VERSION 5.7 ;
BUSBITCHARS "[]" ;
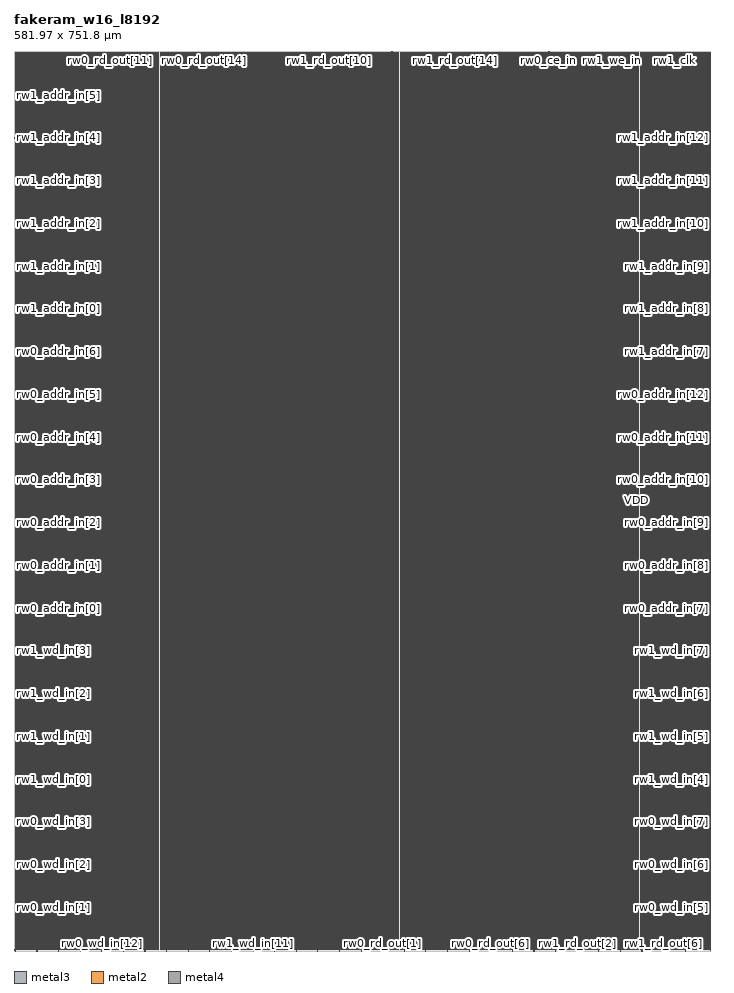
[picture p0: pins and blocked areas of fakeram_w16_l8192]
MACRO fakeram_w16_l8192
  FOREIGN fakeram_w16_l8192 0 0 ;
  SYMMETRY X Y R90 ;
  SIZE 581.970 BY 751.800 ;
  CLASS BLOCK ;
  PIN rw0_wd_in[0]
    DIRECTION INPUT ;
    USE SIGNAL ;
    SHAPE ABUTMENT ;
    PORT
      LAYER metal3 ;
      RECT 0.000 0.805 0.210 0.875 ;
    END
  END rw0_wd_in[0]
  PIN rw0_wd_in[1]
    DIRECTION INPUT ;
    USE SIGNAL ;
    SHAPE ABUTMENT ;
    PORT
      LAYER metal3 ;
      RECT 0.000 36.505 0.210 36.575 ;
    END
  END rw0_wd_in[1]
  PIN rw0_wd_in[2]
    DIRECTION INPUT ;
    USE SIGNAL ;
    SHAPE ABUTMENT ;
    PORT
      LAYER metal3 ;
      RECT 0.000 72.205 0.210 72.275 ;
    END
  END rw0_wd_in[2]
  PIN rw0_wd_in[3]
    DIRECTION INPUT ;
    USE SIGNAL ;
    SHAPE ABUTMENT ;
    PORT
      LAYER metal3 ;
      RECT 0.000 107.905 0.210 107.975 ;
    END
  END rw0_wd_in[3]
  PIN rw0_wd_in[4]
    DIRECTION INPUT ;
    USE SIGNAL ;
    SHAPE ABUTMENT ;
    PORT
      LAYER metal3 ;
      RECT 581.760 0.805 581.970 0.875 ;
    END
  END rw0_wd_in[4]
  PIN rw0_wd_in[5]
    DIRECTION INPUT ;
    USE SIGNAL ;
    SHAPE ABUTMENT ;
    PORT
      LAYER metal3 ;
      RECT 581.760 36.505 581.970 36.575 ;
    END
  END rw0_wd_in[5]
  PIN rw0_wd_in[6]
    DIRECTION INPUT ;
    USE SIGNAL ;
    SHAPE ABUTMENT ;
    PORT
      LAYER metal3 ;
      RECT 581.760 72.205 581.970 72.275 ;
    END
  END rw0_wd_in[6]
  PIN rw0_wd_in[7]
    DIRECTION INPUT ;
    USE SIGNAL ;
    SHAPE ABUTMENT ;
    PORT
      LAYER metal3 ;
      RECT 581.760 107.905 581.970 107.975 ;
    END
  END rw0_wd_in[7]
  PIN rw0_wd_in[8]
    DIRECTION INPUT ;
    USE SIGNAL ;
    SHAPE ABUTMENT ;
    PORT
      LAYER metal2 ;
      RECT 1.105 0.000 1.175 0.210 ;
    END
  END rw0_wd_in[8]
  PIN rw0_wd_in[9]
    DIRECTION INPUT ;
    USE SIGNAL ;
    SHAPE ABUTMENT ;
    PORT
      LAYER metal2 ;
      RECT 19.155 0.000 19.225 0.210 ;
    END
  END rw0_wd_in[9]
  PIN rw0_wd_in[10]
    DIRECTION INPUT ;
    USE SIGNAL ;
    SHAPE ABUTMENT ;
    PORT
      LAYER metal2 ;
      RECT 37.205 0.000 37.275 0.210 ;
    END
  END rw0_wd_in[10]
  PIN rw0_wd_in[11]
    DIRECTION INPUT ;
    USE SIGNAL ;
    SHAPE ABUTMENT ;
    PORT
      LAYER metal2 ;
      RECT 55.255 0.000 55.325 0.210 ;
    END
  END rw0_wd_in[11]
  PIN rw0_wd_in[12]
    DIRECTION INPUT ;
    USE SIGNAL ;
    SHAPE ABUTMENT ;
    PORT
      LAYER metal2 ;
      RECT 73.305 0.000 73.375 0.210 ;
    END
  END rw0_wd_in[12]
  PIN rw0_wd_in[13]
    DIRECTION INPUT ;
    USE SIGNAL ;
    SHAPE ABUTMENT ;
    PORT
      LAYER metal2 ;
      RECT 91.355 0.000 91.425 0.210 ;
    END
  END rw0_wd_in[13]
  PIN rw0_wd_in[14]
    DIRECTION INPUT ;
    USE SIGNAL ;
    SHAPE ABUTMENT ;
    PORT
      LAYER metal2 ;
      RECT 109.405 0.000 109.475 0.210 ;
    END
  END rw0_wd_in[14]
  PIN rw0_wd_in[15]
    DIRECTION INPUT ;
    USE SIGNAL ;
    SHAPE ABUTMENT ;
    PORT
      LAYER metal2 ;
      RECT 127.455 0.000 127.525 0.210 ;
    END
  END rw0_wd_in[15]
  PIN rw1_wd_in[0]
    DIRECTION INPUT ;
    USE SIGNAL ;
    SHAPE ABUTMENT ;
    PORT
      LAYER metal3 ;
      RECT 0.000 143.605 0.210 143.675 ;
    END
  END rw1_wd_in[0]
  PIN rw1_wd_in[1]
    DIRECTION INPUT ;
    USE SIGNAL ;
    SHAPE ABUTMENT ;
    PORT
      LAYER metal3 ;
      RECT 0.000 179.305 0.210 179.375 ;
    END
  END rw1_wd_in[1]
  PIN rw1_wd_in[2]
    DIRECTION INPUT ;
    USE SIGNAL ;
    SHAPE ABUTMENT ;
    PORT
      LAYER metal3 ;
      RECT 0.000 215.005 0.210 215.075 ;
    END
  END rw1_wd_in[2]
  PIN rw1_wd_in[3]
    DIRECTION INPUT ;
    USE SIGNAL ;
    SHAPE ABUTMENT ;
    PORT
      LAYER metal3 ;
      RECT 0.000 250.705 0.210 250.775 ;
    END
  END rw1_wd_in[3]
  PIN rw1_wd_in[4]
    DIRECTION INPUT ;
    USE SIGNAL ;
    SHAPE ABUTMENT ;
    PORT
      LAYER metal3 ;
      RECT 581.760 143.605 581.970 143.675 ;
    END
  END rw1_wd_in[4]
  PIN rw1_wd_in[5]
    DIRECTION INPUT ;
    USE SIGNAL ;
    SHAPE ABUTMENT ;
    PORT
      LAYER metal3 ;
      RECT 581.760 179.305 581.970 179.375 ;
    END
  END rw1_wd_in[5]
  PIN rw1_wd_in[6]
    DIRECTION INPUT ;
    USE SIGNAL ;
    SHAPE ABUTMENT ;
    PORT
      LAYER metal3 ;
      RECT 581.760 215.005 581.970 215.075 ;
    END
  END rw1_wd_in[6]
  PIN rw1_wd_in[7]
    DIRECTION INPUT ;
    USE SIGNAL ;
    SHAPE ABUTMENT ;
    PORT
      LAYER metal3 ;
      RECT 581.760 250.705 581.970 250.775 ;
    END
  END rw1_wd_in[7]
  PIN rw1_wd_in[8]
    DIRECTION INPUT ;
    USE SIGNAL ;
    SHAPE ABUTMENT ;
    PORT
      LAYER metal2 ;
      RECT 145.505 0.000 145.575 0.210 ;
    END
  END rw1_wd_in[8]
  PIN rw1_wd_in[9]
    DIRECTION INPUT ;
    USE SIGNAL ;
    SHAPE ABUTMENT ;
    PORT
      LAYER metal2 ;
      RECT 163.555 0.000 163.625 0.210 ;
    END
  END rw1_wd_in[9]
  PIN rw1_wd_in[10]
    DIRECTION INPUT ;
    USE SIGNAL ;
    SHAPE ABUTMENT ;
    PORT
      LAYER metal2 ;
      RECT 181.605 0.000 181.675 0.210 ;
    END
  END rw1_wd_in[10]
  PIN rw1_wd_in[11]
    DIRECTION INPUT ;
    USE SIGNAL ;
    SHAPE ABUTMENT ;
    PORT
      LAYER metal2 ;
      RECT 199.655 0.000 199.725 0.210 ;
    END
  END rw1_wd_in[11]
  PIN rw1_wd_in[12]
    DIRECTION INPUT ;
    USE SIGNAL ;
    SHAPE ABUTMENT ;
    PORT
      LAYER metal2 ;
      RECT 217.705 0.000 217.775 0.210 ;
    END
  END rw1_wd_in[12]
  PIN rw1_wd_in[13]
    DIRECTION INPUT ;
    USE SIGNAL ;
    SHAPE ABUTMENT ;
    PORT
      LAYER metal2 ;
      RECT 235.755 0.000 235.825 0.210 ;
    END
  END rw1_wd_in[13]
  PIN rw1_wd_in[14]
    DIRECTION INPUT ;
    USE SIGNAL ;
    SHAPE ABUTMENT ;
    PORT
      LAYER metal2 ;
      RECT 253.805 0.000 253.875 0.210 ;
    END
  END rw1_wd_in[14]
  PIN rw1_wd_in[15]
    DIRECTION INPUT ;
    USE SIGNAL ;
    SHAPE ABUTMENT ;
    PORT
      LAYER metal2 ;
      RECT 271.855 0.000 271.925 0.210 ;
    END
  END rw1_wd_in[15]
  PIN rw0_rd_out[0]
    DIRECTION OUTPUT ;
    USE SIGNAL ;
    SHAPE ABUTMENT ;
    PORT
      LAYER metal2 ;
      RECT 289.905 0.000 289.975 0.210 ;
    END
  END rw0_rd_out[0]
  PIN rw0_rd_out[1]
    DIRECTION OUTPUT ;
    USE SIGNAL ;
    SHAPE ABUTMENT ;
    PORT
      LAYER metal2 ;
      RECT 307.955 0.000 308.025 0.210 ;
    END
  END rw0_rd_out[1]
  PIN rw0_rd_out[2]
    DIRECTION OUTPUT ;
    USE SIGNAL ;
    SHAPE ABUTMENT ;
    PORT
      LAYER metal2 ;
      RECT 326.005 0.000 326.075 0.210 ;
    END
  END rw0_rd_out[2]
  PIN rw0_rd_out[3]
    DIRECTION OUTPUT ;
    USE SIGNAL ;
    SHAPE ABUTMENT ;
    PORT
      LAYER metal2 ;
      RECT 344.055 0.000 344.125 0.210 ;
    END
  END rw0_rd_out[3]
  PIN rw0_rd_out[4]
    DIRECTION OUTPUT ;
    USE SIGNAL ;
    SHAPE ABUTMENT ;
    PORT
      LAYER metal2 ;
      RECT 362.105 0.000 362.175 0.210 ;
    END
  END rw0_rd_out[4]
  PIN rw0_rd_out[5]
    DIRECTION OUTPUT ;
    USE SIGNAL ;
    SHAPE ABUTMENT ;
    PORT
      LAYER metal2 ;
      RECT 380.155 0.000 380.225 0.210 ;
    END
  END rw0_rd_out[5]
  PIN rw0_rd_out[6]
    DIRECTION OUTPUT ;
    USE SIGNAL ;
    SHAPE ABUTMENT ;
    PORT
      LAYER metal2 ;
      RECT 398.205 0.000 398.275 0.210 ;
    END
  END rw0_rd_out[6]
  PIN rw0_rd_out[7]
    DIRECTION OUTPUT ;
    USE SIGNAL ;
    SHAPE ABUTMENT ;
    PORT
      LAYER metal2 ;
      RECT 416.255 0.000 416.325 0.210 ;
    END
  END rw0_rd_out[7]
  PIN rw0_rd_out[8]
    DIRECTION OUTPUT ;
    USE SIGNAL ;
    SHAPE ABUTMENT ;
    PORT
      LAYER metal2 ;
      RECT 1.105 751.590 1.175 751.800 ;
    END
  END rw0_rd_out[8]
  PIN rw0_rd_out[9]
    DIRECTION OUTPUT ;
    USE SIGNAL ;
    SHAPE ABUTMENT ;
    PORT
      LAYER metal2 ;
      RECT 27.325 751.590 27.395 751.800 ;
    END
  END rw0_rd_out[9]
  PIN rw0_rd_out[10]
    DIRECTION OUTPUT ;
    USE SIGNAL ;
    SHAPE ABUTMENT ;
    PORT
      LAYER metal2 ;
      RECT 53.545 751.590 53.615 751.800 ;
    END
  END rw0_rd_out[10]
  PIN rw0_rd_out[11]
    DIRECTION OUTPUT ;
    USE SIGNAL ;
    SHAPE ABUTMENT ;
    PORT
      LAYER metal2 ;
      RECT 79.765 751.590 79.835 751.800 ;
    END
  END rw0_rd_out[11]
  PIN rw0_rd_out[12]
    DIRECTION OUTPUT ;
    USE SIGNAL ;
    SHAPE ABUTMENT ;
    PORT
      LAYER metal2 ;
      RECT 105.985 751.590 106.055 751.800 ;
    END
  END rw0_rd_out[12]
  PIN rw0_rd_out[13]
    DIRECTION OUTPUT ;
    USE SIGNAL ;
    SHAPE ABUTMENT ;
    PORT
      LAYER metal2 ;
      RECT 132.205 751.590 132.275 751.800 ;
    END
  END rw0_rd_out[13]
  PIN rw0_rd_out[14]
    DIRECTION OUTPUT ;
    USE SIGNAL ;
    SHAPE ABUTMENT ;
    PORT
      LAYER metal2 ;
      RECT 158.425 751.590 158.495 751.800 ;
    END
  END rw0_rd_out[14]
  PIN rw0_rd_out[15]
    DIRECTION OUTPUT ;
    USE SIGNAL ;
    SHAPE ABUTMENT ;
    PORT
      LAYER metal2 ;
      RECT 184.645 751.590 184.715 751.800 ;
    END
  END rw0_rd_out[15]
  PIN rw1_rd_out[0]
    DIRECTION OUTPUT ;
    USE SIGNAL ;
    SHAPE ABUTMENT ;
    PORT
      LAYER metal2 ;
      RECT 434.305 0.000 434.375 0.210 ;
    END
  END rw1_rd_out[0]
  PIN rw1_rd_out[1]
    DIRECTION OUTPUT ;
    USE SIGNAL ;
    SHAPE ABUTMENT ;
    PORT
      LAYER metal2 ;
      RECT 452.355 0.000 452.425 0.210 ;
    END
  END rw1_rd_out[1]
  PIN rw1_rd_out[2]
    DIRECTION OUTPUT ;
    USE SIGNAL ;
    SHAPE ABUTMENT ;
    PORT
      LAYER metal2 ;
      RECT 470.405 0.000 470.475 0.210 ;
    END
  END rw1_rd_out[2]
  PIN rw1_rd_out[3]
    DIRECTION OUTPUT ;
    USE SIGNAL ;
    SHAPE ABUTMENT ;
    PORT
      LAYER metal2 ;
      RECT 488.455 0.000 488.525 0.210 ;
    END
  END rw1_rd_out[3]
  PIN rw1_rd_out[4]
    DIRECTION OUTPUT ;
    USE SIGNAL ;
    SHAPE ABUTMENT ;
    PORT
      LAYER metal2 ;
      RECT 506.505 0.000 506.575 0.210 ;
    END
  END rw1_rd_out[4]
  PIN rw1_rd_out[5]
    DIRECTION OUTPUT ;
    USE SIGNAL ;
    SHAPE ABUTMENT ;
    PORT
      LAYER metal2 ;
      RECT 524.555 0.000 524.625 0.210 ;
    END
  END rw1_rd_out[5]
  PIN rw1_rd_out[6]
    DIRECTION OUTPUT ;
    USE SIGNAL ;
    SHAPE ABUTMENT ;
    PORT
      LAYER metal2 ;
      RECT 542.605 0.000 542.675 0.210 ;
    END
  END rw1_rd_out[6]
  PIN rw1_rd_out[7]
    DIRECTION OUTPUT ;
    USE SIGNAL ;
    SHAPE ABUTMENT ;
    PORT
      LAYER metal2 ;
      RECT 560.655 0.000 560.725 0.210 ;
    END
  END rw1_rd_out[7]
  PIN rw1_rd_out[8]
    DIRECTION OUTPUT ;
    USE SIGNAL ;
    SHAPE ABUTMENT ;
    PORT
      LAYER metal2 ;
      RECT 210.865 751.590 210.935 751.800 ;
    END
  END rw1_rd_out[8]
  PIN rw1_rd_out[9]
    DIRECTION OUTPUT ;
    USE SIGNAL ;
    SHAPE ABUTMENT ;
    PORT
      LAYER metal2 ;
      RECT 237.085 751.590 237.155 751.800 ;
    END
  END rw1_rd_out[9]
  PIN rw1_rd_out[10]
    DIRECTION OUTPUT ;
    USE SIGNAL ;
    SHAPE ABUTMENT ;
    PORT
      LAYER metal2 ;
      RECT 263.305 751.590 263.375 751.800 ;
    END
  END rw1_rd_out[10]
  PIN rw1_rd_out[11]
    DIRECTION OUTPUT ;
    USE SIGNAL ;
    SHAPE ABUTMENT ;
    PORT
      LAYER metal2 ;
      RECT 289.525 751.590 289.595 751.800 ;
    END
  END rw1_rd_out[11]
  PIN rw1_rd_out[12]
    DIRECTION OUTPUT ;
    USE SIGNAL ;
    SHAPE ABUTMENT ;
    PORT
      LAYER metal2 ;
      RECT 315.745 751.590 315.815 751.800 ;
    END
  END rw1_rd_out[12]
  PIN rw1_rd_out[13]
    DIRECTION OUTPUT ;
    USE SIGNAL ;
    SHAPE ABUTMENT ;
    PORT
      LAYER metal2 ;
      RECT 341.965 751.590 342.035 751.800 ;
    END
  END rw1_rd_out[13]
  PIN rw1_rd_out[14]
    DIRECTION OUTPUT ;
    USE SIGNAL ;
    SHAPE ABUTMENT ;
    PORT
      LAYER metal2 ;
      RECT 368.185 751.590 368.255 751.800 ;
    END
  END rw1_rd_out[14]
  PIN rw1_rd_out[15]
    DIRECTION OUTPUT ;
    USE SIGNAL ;
    SHAPE ABUTMENT ;
    PORT
      LAYER metal2 ;
      RECT 394.405 751.590 394.475 751.800 ;
    END
  END rw1_rd_out[15]
  PIN rw0_addr_in[0]
    DIRECTION INPUT ;
    USE SIGNAL ;
    SHAPE ABUTMENT ;
    PORT
      LAYER metal3 ;
      RECT 0.000 286.405 0.210 286.475 ;
    END
  END rw0_addr_in[0]
  PIN rw0_addr_in[1]
    DIRECTION INPUT ;
    USE SIGNAL ;
    SHAPE ABUTMENT ;
    PORT
      LAYER metal3 ;
      RECT 0.000 322.105 0.210 322.175 ;
    END
  END rw0_addr_in[1]
  PIN rw0_addr_in[2]
    DIRECTION INPUT ;
    USE SIGNAL ;
    SHAPE ABUTMENT ;
    PORT
      LAYER metal3 ;
      RECT 0.000 357.805 0.210 357.875 ;
    END
  END rw0_addr_in[2]
  PIN rw0_addr_in[3]
    DIRECTION INPUT ;
    USE SIGNAL ;
    SHAPE ABUTMENT ;
    PORT
      LAYER metal3 ;
      RECT 0.000 393.505 0.210 393.575 ;
    END
  END rw0_addr_in[3]
  PIN rw0_addr_in[4]
    DIRECTION INPUT ;
    USE SIGNAL ;
    SHAPE ABUTMENT ;
    PORT
      LAYER metal3 ;
      RECT 0.000 429.205 0.210 429.275 ;
    END
  END rw0_addr_in[4]
  PIN rw0_addr_in[5]
    DIRECTION INPUT ;
    USE SIGNAL ;
    SHAPE ABUTMENT ;
    PORT
      LAYER metal3 ;
      RECT 0.000 464.905 0.210 464.975 ;
    END
  END rw0_addr_in[5]
  PIN rw0_addr_in[6]
    DIRECTION INPUT ;
    USE SIGNAL ;
    SHAPE ABUTMENT ;
    PORT
      LAYER metal3 ;
      RECT 0.000 500.605 0.210 500.675 ;
    END
  END rw0_addr_in[6]
  PIN rw0_addr_in[7]
    DIRECTION INPUT ;
    USE SIGNAL ;
    SHAPE ABUTMENT ;
    PORT
      LAYER metal3 ;
      RECT 581.760 286.405 581.970 286.475 ;
    END
  END rw0_addr_in[7]
  PIN rw0_addr_in[8]
    DIRECTION INPUT ;
    USE SIGNAL ;
    SHAPE ABUTMENT ;
    PORT
      LAYER metal3 ;
      RECT 581.760 322.105 581.970 322.175 ;
    END
  END rw0_addr_in[8]
  PIN rw0_addr_in[9]
    DIRECTION INPUT ;
    USE SIGNAL ;
    SHAPE ABUTMENT ;
    PORT
      LAYER metal3 ;
      RECT 581.760 357.805 581.970 357.875 ;
    END
  END rw0_addr_in[9]
  PIN rw0_addr_in[10]
    DIRECTION INPUT ;
    USE SIGNAL ;
    SHAPE ABUTMENT ;
    PORT
      LAYER metal3 ;
      RECT 581.760 393.505 581.970 393.575 ;
    END
  END rw0_addr_in[10]
  PIN rw0_addr_in[11]
    DIRECTION INPUT ;
    USE SIGNAL ;
    SHAPE ABUTMENT ;
    PORT
      LAYER metal3 ;
      RECT 581.760 429.205 581.970 429.275 ;
    END
  END rw0_addr_in[11]
  PIN rw0_addr_in[12]
    DIRECTION INPUT ;
    USE SIGNAL ;
    SHAPE ABUTMENT ;
    PORT
      LAYER metal3 ;
      RECT 581.760 464.905 581.970 464.975 ;
    END
  END rw0_addr_in[12]
  PIN rw1_addr_in[0]
    DIRECTION INPUT ;
    USE SIGNAL ;
    SHAPE ABUTMENT ;
    PORT
      LAYER metal3 ;
      RECT 0.000 536.305 0.210 536.375 ;
    END
  END rw1_addr_in[0]
  PIN rw1_addr_in[1]
    DIRECTION INPUT ;
    USE SIGNAL ;
    SHAPE ABUTMENT ;
    PORT
      LAYER metal3 ;
      RECT 0.000 572.005 0.210 572.075 ;
    END
  END rw1_addr_in[1]
  PIN rw1_addr_in[2]
    DIRECTION INPUT ;
    USE SIGNAL ;
    SHAPE ABUTMENT ;
    PORT
      LAYER metal3 ;
      RECT 0.000 607.705 0.210 607.775 ;
    END
  END rw1_addr_in[2]
  PIN rw1_addr_in[3]
    DIRECTION INPUT ;
    USE SIGNAL ;
    SHAPE ABUTMENT ;
    PORT
      LAYER metal3 ;
      RECT 0.000 643.405 0.210 643.475 ;
    END
  END rw1_addr_in[3]
  PIN rw1_addr_in[4]
    DIRECTION INPUT ;
    USE SIGNAL ;
    SHAPE ABUTMENT ;
    PORT
      LAYER metal3 ;
      RECT 0.000 679.105 0.210 679.175 ;
    END
  END rw1_addr_in[4]
  PIN rw1_addr_in[5]
    DIRECTION INPUT ;
    USE SIGNAL ;
    SHAPE ABUTMENT ;
    PORT
      LAYER metal3 ;
      RECT 0.000 714.805 0.210 714.875 ;
    END
  END rw1_addr_in[5]
  PIN rw1_addr_in[6]
    DIRECTION INPUT ;
    USE SIGNAL ;
    SHAPE ABUTMENT ;
    PORT
      LAYER metal3 ;
      RECT 0.000 750.505 0.210 750.575 ;
    END
  END rw1_addr_in[6]
  PIN rw1_addr_in[7]
    DIRECTION INPUT ;
    USE SIGNAL ;
    SHAPE ABUTMENT ;
    PORT
      LAYER metal3 ;
      RECT 581.760 500.605 581.970 500.675 ;
    END
  END rw1_addr_in[7]
  PIN rw1_addr_in[8]
    DIRECTION INPUT ;
    USE SIGNAL ;
    SHAPE ABUTMENT ;
    PORT
      LAYER metal3 ;
      RECT 581.760 536.305 581.970 536.375 ;
    END
  END rw1_addr_in[8]
  PIN rw1_addr_in[9]
    DIRECTION INPUT ;
    USE SIGNAL ;
    SHAPE ABUTMENT ;
    PORT
      LAYER metal3 ;
      RECT 581.760 572.005 581.970 572.075 ;
    END
  END rw1_addr_in[9]
  PIN rw1_addr_in[10]
    DIRECTION INPUT ;
    USE SIGNAL ;
    SHAPE ABUTMENT ;
    PORT
      LAYER metal3 ;
      RECT 581.760 607.705 581.970 607.775 ;
    END
  END rw1_addr_in[10]
  PIN rw1_addr_in[11]
    DIRECTION INPUT ;
    USE SIGNAL ;
    SHAPE ABUTMENT ;
    PORT
      LAYER metal3 ;
      RECT 581.760 643.405 581.970 643.475 ;
    END
  END rw1_addr_in[11]
  PIN rw1_addr_in[12]
    DIRECTION INPUT ;
    USE SIGNAL ;
    SHAPE ABUTMENT ;
    PORT
      LAYER metal3 ;
      RECT 581.760 679.105 581.970 679.175 ;
    END
  END rw1_addr_in[12]
  PIN rw0_we_in
    DIRECTION INPUT ;
    USE SIGNAL ;
    SHAPE ABUTMENT ;
    PORT
      LAYER metal2 ;
      RECT 420.625 751.590 420.695 751.800 ;
    END
  END rw0_we_in
  PIN rw0_ce_in
    DIRECTION INPUT ;
    USE SIGNAL ;
    SHAPE ABUTMENT ;
    PORT
      LAYER metal2 ;
      RECT 446.845 751.590 446.915 751.800 ;
    END
  END rw0_ce_in
  PIN rw0_clk
    DIRECTION INPUT ;
    USE SIGNAL ;
    SHAPE ABUTMENT ;
    PORT
      LAYER metal2 ;
      RECT 473.065 751.590 473.135 751.800 ;
    END
  END rw0_clk
  PIN rw1_we_in
    DIRECTION INPUT ;
    USE SIGNAL ;
    SHAPE ABUTMENT ;
    PORT
      LAYER metal2 ;
      RECT 499.285 751.590 499.355 751.800 ;
    END
  END rw1_we_in
  PIN rw1_ce_in
    DIRECTION INPUT ;
    USE SIGNAL ;
    SHAPE ABUTMENT ;
    PORT
      LAYER metal2 ;
      RECT 525.505 751.590 525.575 751.800 ;
    END
  END rw1_ce_in
  PIN rw1_clk
    DIRECTION INPUT ;
    USE SIGNAL ;
    SHAPE ABUTMENT ;
    PORT
      LAYER metal2 ;
      RECT 551.725 751.590 551.795 751.800 ;
    END
  END rw1_clk
  PIN VSS
    DIRECTION INOUT ;
    USE GROUND ;
    PORT
      LAYER metal4 ;
      RECT 1.000 0.840 1.280 750.960 ;
      RECT 3.240 0.840 3.520 750.960 ;
      RECT 5.480 0.840 5.760 750.960 ;
      RECT 7.720 0.840 8.000 750.960 ;
      RECT 9.960 0.840 10.240 750.960 ;
      RECT 12.200 0.840 12.480 750.960 ;
      RECT 14.440 0.840 14.720 750.960 ;
      RECT 16.680 0.840 16.960 750.960 ;
      RECT 18.920 0.840 19.200 750.960 ;
      RECT 21.160 0.840 21.440 750.960 ;
      RECT 23.400 0.840 23.680 750.960 ;
      RECT 25.640 0.840 25.920 750.960 ;
      RECT 27.880 0.840 28.160 750.960 ;
      RECT 30.120 0.840 30.400 750.960 ;
      RECT 32.360 0.840 32.640 750.960 ;
      RECT 34.600 0.840 34.880 750.960 ;
      RECT 36.840 0.840 37.120 750.960 ;
      RECT 39.080 0.840 39.360 750.960 ;
      RECT 41.320 0.840 41.600 750.960 ;
      RECT 43.560 0.840 43.840 750.960 ;
      RECT 45.800 0.840 46.080 750.960 ;
      RECT 48.040 0.840 48.320 750.960 ;
      RECT 50.280 0.840 50.560 750.960 ;
      RECT 52.520 0.840 52.800 750.960 ;
      RECT 54.760 0.840 55.040 750.960 ;
      RECT 57.000 0.840 57.280 750.960 ;
      RECT 59.240 0.840 59.520 750.960 ;
      RECT 61.480 0.840 61.760 750.960 ;
      RECT 63.720 0.840 64.000 750.960 ;
      RECT 65.960 0.840 66.240 750.960 ;
      RECT 68.200 0.840 68.480 750.960 ;
      RECT 70.440 0.840 70.720 750.960 ;
      RECT 72.680 0.840 72.960 750.960 ;
      RECT 74.920 0.840 75.200 750.960 ;
      RECT 77.160 0.840 77.440 750.960 ;
      RECT 79.400 0.840 79.680 750.960 ;
      RECT 81.640 0.840 81.920 750.960 ;
      RECT 83.880 0.840 84.160 750.960 ;
      RECT 86.120 0.840 86.400 750.960 ;
      RECT 88.360 0.840 88.640 750.960 ;
      RECT 90.600 0.840 90.880 750.960 ;
      RECT 92.840 0.840 93.120 750.960 ;
      RECT 95.080 0.840 95.360 750.960 ;
      RECT 97.320 0.840 97.600 750.960 ;
      RECT 99.560 0.840 99.840 750.960 ;
      RECT 101.800 0.840 102.080 750.960 ;
      RECT 104.040 0.840 104.320 750.960 ;
      RECT 106.280 0.840 106.560 750.960 ;
      RECT 108.520 0.840 108.800 750.960 ;
      RECT 110.760 0.840 111.040 750.960 ;
      RECT 113.000 0.840 113.280 750.960 ;
      RECT 115.240 0.840 115.520 750.960 ;
      RECT 117.480 0.840 117.760 750.960 ;
      RECT 119.720 0.840 120.000 750.960 ;
      RECT 121.960 0.840 122.240 750.960 ;
      RECT 124.200 0.840 124.480 750.960 ;
      RECT 126.440 0.840 126.720 750.960 ;
      RECT 128.680 0.840 128.960 750.960 ;
      RECT 130.920 0.840 131.200 750.960 ;
      RECT 133.160 0.840 133.440 750.960 ;
      RECT 135.400 0.840 135.680 750.960 ;
      RECT 137.640 0.840 137.920 750.960 ;
      RECT 139.880 0.840 140.160 750.960 ;
      RECT 142.120 0.840 142.400 750.960 ;
      RECT 144.360 0.840 144.640 750.960 ;
      RECT 146.600 0.840 146.880 750.960 ;
      RECT 148.840 0.840 149.120 750.960 ;
      RECT 151.080 0.840 151.360 750.960 ;
      RECT 153.320 0.840 153.600 750.960 ;
      RECT 155.560 0.840 155.840 750.960 ;
      RECT 157.800 0.840 158.080 750.960 ;
      RECT 160.040 0.840 160.320 750.960 ;
      RECT 162.280 0.840 162.560 750.960 ;
      RECT 164.520 0.840 164.800 750.960 ;
      RECT 166.760 0.840 167.040 750.960 ;
      RECT 169.000 0.840 169.280 750.960 ;
      RECT 171.240 0.840 171.520 750.960 ;
      RECT 173.480 0.840 173.760 750.960 ;
      RECT 175.720 0.840 176.000 750.960 ;
      RECT 177.960 0.840 178.240 750.960 ;
      RECT 180.200 0.840 180.480 750.960 ;
      RECT 182.440 0.840 182.720 750.960 ;
      RECT 184.680 0.840 184.960 750.960 ;
      RECT 186.920 0.840 187.200 750.960 ;
      RECT 189.160 0.840 189.440 750.960 ;
      RECT 191.400 0.840 191.680 750.960 ;
      RECT 193.640 0.840 193.920 750.960 ;
      RECT 195.880 0.840 196.160 750.960 ;
      RECT 198.120 0.840 198.400 750.960 ;
      RECT 200.360 0.840 200.640 750.960 ;
      RECT 202.600 0.840 202.880 750.960 ;
      RECT 204.840 0.840 205.120 750.960 ;
      RECT 207.080 0.840 207.360 750.960 ;
      RECT 209.320 0.840 209.600 750.960 ;
      RECT 211.560 0.840 211.840 750.960 ;
      RECT 213.800 0.840 214.080 750.960 ;
      RECT 216.040 0.840 216.320 750.960 ;
      RECT 218.280 0.840 218.560 750.960 ;
      RECT 220.520 0.840 220.800 750.960 ;
      RECT 222.760 0.840 223.040 750.960 ;
      RECT 225.000 0.840 225.280 750.960 ;
      RECT 227.240 0.840 227.520 750.960 ;
      RECT 229.480 0.840 229.760 750.960 ;
      RECT 231.720 0.840 232.000 750.960 ;
      RECT 233.960 0.840 234.240 750.960 ;
      RECT 236.200 0.840 236.480 750.960 ;
      RECT 238.440 0.840 238.720 750.960 ;
      RECT 240.680 0.840 240.960 750.960 ;
      RECT 242.920 0.840 243.200 750.960 ;
      RECT 245.160 0.840 245.440 750.960 ;
      RECT 247.400 0.840 247.680 750.960 ;
      RECT 249.640 0.840 249.920 750.960 ;
      RECT 251.880 0.840 252.160 750.960 ;
      RECT 254.120 0.840 254.400 750.960 ;
      RECT 256.360 0.840 256.640 750.960 ;
      RECT 258.600 0.840 258.880 750.960 ;
      RECT 260.840 0.840 261.120 750.960 ;
      RECT 263.080 0.840 263.360 750.960 ;
      RECT 265.320 0.840 265.600 750.960 ;
      RECT 267.560 0.840 267.840 750.960 ;
      RECT 269.800 0.840 270.080 750.960 ;
      RECT 272.040 0.840 272.320 750.960 ;
      RECT 274.280 0.840 274.560 750.960 ;
      RECT 276.520 0.840 276.800 750.960 ;
      RECT 278.760 0.840 279.040 750.960 ;
      RECT 281.000 0.840 281.280 750.960 ;
      RECT 283.240 0.840 283.520 750.960 ;
      RECT 285.480 0.840 285.760 750.960 ;
      RECT 287.720 0.840 288.000 750.960 ;
      RECT 289.960 0.840 290.240 750.960 ;
      RECT 292.200 0.840 292.480 750.960 ;
      RECT 294.440 0.840 294.720 750.960 ;
      RECT 296.680 0.840 296.960 750.960 ;
      RECT 298.920 0.840 299.200 750.960 ;
      RECT 301.160 0.840 301.440 750.960 ;
      RECT 303.400 0.840 303.680 750.960 ;
      RECT 305.640 0.840 305.920 750.960 ;
      RECT 307.880 0.840 308.160 750.960 ;
      RECT 310.120 0.840 310.400 750.960 ;
      RECT 312.360 0.840 312.640 750.960 ;
      RECT 314.600 0.840 314.880 750.960 ;
      RECT 316.840 0.840 317.120 750.960 ;
      RECT 319.080 0.840 319.360 750.960 ;
      RECT 321.320 0.840 321.600 750.960 ;
      RECT 323.560 0.840 323.840 750.960 ;
      RECT 325.800 0.840 326.080 750.960 ;
      RECT 328.040 0.840 328.320 750.960 ;
      RECT 330.280 0.840 330.560 750.960 ;
      RECT 332.520 0.840 332.800 750.960 ;
      RECT 334.760 0.840 335.040 750.960 ;
      RECT 337.000 0.840 337.280 750.960 ;
      RECT 339.240 0.840 339.520 750.960 ;
      RECT 341.480 0.840 341.760 750.960 ;
      RECT 343.720 0.840 344.000 750.960 ;
      RECT 345.960 0.840 346.240 750.960 ;
      RECT 348.200 0.840 348.480 750.960 ;
      RECT 350.440 0.840 350.720 750.960 ;
      RECT 352.680 0.840 352.960 750.960 ;
      RECT 354.920 0.840 355.200 750.960 ;
      RECT 357.160 0.840 357.440 750.960 ;
      RECT 359.400 0.840 359.680 750.960 ;
      RECT 361.640 0.840 361.920 750.960 ;
      RECT 363.880 0.840 364.160 750.960 ;
      RECT 366.120 0.840 366.400 750.960 ;
      RECT 368.360 0.840 368.640 750.960 ;
      RECT 370.600 0.840 370.880 750.960 ;
      RECT 372.840 0.840 373.120 750.960 ;
      RECT 375.080 0.840 375.360 750.960 ;
      RECT 377.320 0.840 377.600 750.960 ;
      RECT 379.560 0.840 379.840 750.960 ;
      RECT 381.800 0.840 382.080 750.960 ;
      RECT 384.040 0.840 384.320 750.960 ;
      RECT 386.280 0.840 386.560 750.960 ;
      RECT 388.520 0.840 388.800 750.960 ;
      RECT 390.760 0.840 391.040 750.960 ;
      RECT 393.000 0.840 393.280 750.960 ;
      RECT 395.240 0.840 395.520 750.960 ;
      RECT 397.480 0.840 397.760 750.960 ;
      RECT 399.720 0.840 400.000 750.960 ;
      RECT 401.960 0.840 402.240 750.960 ;
      RECT 404.200 0.840 404.480 750.960 ;
      RECT 406.440 0.840 406.720 750.960 ;
      RECT 408.680 0.840 408.960 750.960 ;
      RECT 410.920 0.840 411.200 750.960 ;
      RECT 413.160 0.840 413.440 750.960 ;
      RECT 415.400 0.840 415.680 750.960 ;
      RECT 417.640 0.840 417.920 750.960 ;
      RECT 419.880 0.840 420.160 750.960 ;
      RECT 422.120 0.840 422.400 750.960 ;
      RECT 424.360 0.840 424.640 750.960 ;
      RECT 426.600 0.840 426.880 750.960 ;
      RECT 428.840 0.840 429.120 750.960 ;
      RECT 431.080 0.840 431.360 750.960 ;
      RECT 433.320 0.840 433.600 750.960 ;
      RECT 435.560 0.840 435.840 750.960 ;
      RECT 437.800 0.840 438.080 750.960 ;
      RECT 440.040 0.840 440.320 750.960 ;
      RECT 442.280 0.840 442.560 750.960 ;
      RECT 444.520 0.840 444.800 750.960 ;
      RECT 446.760 0.840 447.040 750.960 ;
      RECT 449.000 0.840 449.280 750.960 ;
      RECT 451.240 0.840 451.520 750.960 ;
      RECT 453.480 0.840 453.760 750.960 ;
      RECT 455.720 0.840 456.000 750.960 ;
      RECT 457.960 0.840 458.240 750.960 ;
      RECT 460.200 0.840 460.480 750.960 ;
      RECT 462.440 0.840 462.720 750.960 ;
      RECT 464.680 0.840 464.960 750.960 ;
      RECT 466.920 0.840 467.200 750.960 ;
      RECT 469.160 0.840 469.440 750.960 ;
      RECT 471.400 0.840 471.680 750.960 ;
      RECT 473.640 0.840 473.920 750.960 ;
      RECT 475.880 0.840 476.160 750.960 ;
      RECT 478.120 0.840 478.400 750.960 ;
      RECT 480.360 0.840 480.640 750.960 ;
      RECT 482.600 0.840 482.880 750.960 ;
      RECT 484.840 0.840 485.120 750.960 ;
      RECT 487.080 0.840 487.360 750.960 ;
      RECT 489.320 0.840 489.600 750.960 ;
      RECT 491.560 0.840 491.840 750.960 ;
      RECT 493.800 0.840 494.080 750.960 ;
      RECT 496.040 0.840 496.320 750.960 ;
      RECT 498.280 0.840 498.560 750.960 ;
      RECT 500.520 0.840 500.800 750.960 ;
      RECT 502.760 0.840 503.040 750.960 ;
      RECT 505.000 0.840 505.280 750.960 ;
      RECT 507.240 0.840 507.520 750.960 ;
      RECT 509.480 0.840 509.760 750.960 ;
      RECT 511.720 0.840 512.000 750.960 ;
      RECT 513.960 0.840 514.240 750.960 ;
      RECT 516.200 0.840 516.480 750.960 ;
      RECT 518.440 0.840 518.720 750.960 ;
      RECT 520.680 0.840 520.960 750.960 ;
      RECT 522.920 0.840 523.200 750.960 ;
      RECT 525.160 0.840 525.440 750.960 ;
      RECT 527.400 0.840 527.680 750.960 ;
      RECT 529.640 0.840 529.920 750.960 ;
      RECT 531.880 0.840 532.160 750.960 ;
      RECT 534.120 0.840 534.400 750.960 ;
      RECT 536.360 0.840 536.640 750.960 ;
      RECT 538.600 0.840 538.880 750.960 ;
      RECT 540.840 0.840 541.120 750.960 ;
      RECT 543.080 0.840 543.360 750.960 ;
      RECT 545.320 0.840 545.600 750.960 ;
      RECT 547.560 0.840 547.840 750.960 ;
      RECT 549.800 0.840 550.080 750.960 ;
      RECT 552.040 0.840 552.320 750.960 ;
      RECT 554.280 0.840 554.560 750.960 ;
      RECT 556.520 0.840 556.800 750.960 ;
      RECT 558.760 0.840 559.040 750.960 ;
      RECT 561.000 0.840 561.280 750.960 ;
      RECT 563.240 0.840 563.520 750.960 ;
      RECT 565.480 0.840 565.760 750.960 ;
      RECT 567.720 0.840 568.000 750.960 ;
      RECT 569.960 0.840 570.240 750.960 ;
      RECT 572.200 0.840 572.480 750.960 ;
      RECT 574.440 0.840 574.720 750.960 ;
      RECT 576.680 0.840 576.960 750.960 ;
      RECT 578.920 0.840 579.200 750.960 ;
      RECT 581.160 0.840 581.440 750.960 ;
    END
  END VSS
  PIN VDD
    DIRECTION INOUT ;
    USE POWER ;
    PORT
      LAYER metal4 ;
      RECT 2.120 0.840 2.400 750.960 ;
      RECT 4.360 0.840 4.640 750.960 ;
      RECT 6.600 0.840 6.880 750.960 ;
      RECT 8.840 0.840 9.120 750.960 ;
      RECT 11.080 0.840 11.360 750.960 ;
      RECT 13.320 0.840 13.600 750.960 ;
      RECT 15.560 0.840 15.840 750.960 ;
      RECT 17.800 0.840 18.080 750.960 ;
      RECT 20.040 0.840 20.320 750.960 ;
      RECT 22.280 0.840 22.560 750.960 ;
      RECT 24.520 0.840 24.800 750.960 ;
      RECT 26.760 0.840 27.040 750.960 ;
      RECT 29.000 0.840 29.280 750.960 ;
      RECT 31.240 0.840 31.520 750.960 ;
      RECT 33.480 0.840 33.760 750.960 ;
      RECT 35.720 0.840 36.000 750.960 ;
      RECT 37.960 0.840 38.240 750.960 ;
      RECT 40.200 0.840 40.480 750.960 ;
      RECT 42.440 0.840 42.720 750.960 ;
      RECT 44.680 0.840 44.960 750.960 ;
      RECT 46.920 0.840 47.200 750.960 ;
      RECT 49.160 0.840 49.440 750.960 ;
      RECT 51.400 0.840 51.680 750.960 ;
      RECT 53.640 0.840 53.920 750.960 ;
      RECT 55.880 0.840 56.160 750.960 ;
      RECT 58.120 0.840 58.400 750.960 ;
      RECT 60.360 0.840 60.640 750.960 ;
      RECT 62.600 0.840 62.880 750.960 ;
      RECT 64.840 0.840 65.120 750.960 ;
      RECT 67.080 0.840 67.360 750.960 ;
      RECT 69.320 0.840 69.600 750.960 ;
      RECT 71.560 0.840 71.840 750.960 ;
      RECT 73.800 0.840 74.080 750.960 ;
      RECT 76.040 0.840 76.320 750.960 ;
      RECT 78.280 0.840 78.560 750.960 ;
      RECT 80.520 0.840 80.800 750.960 ;
      RECT 82.760 0.840 83.040 750.960 ;
      RECT 85.000 0.840 85.280 750.960 ;
      RECT 87.240 0.840 87.520 750.960 ;
      RECT 89.480 0.840 89.760 750.960 ;
      RECT 91.720 0.840 92.000 750.960 ;
      RECT 93.960 0.840 94.240 750.960 ;
      RECT 96.200 0.840 96.480 750.960 ;
      RECT 98.440 0.840 98.720 750.960 ;
      RECT 100.680 0.840 100.960 750.960 ;
      RECT 102.920 0.840 103.200 750.960 ;
      RECT 105.160 0.840 105.440 750.960 ;
      RECT 107.400 0.840 107.680 750.960 ;
      RECT 109.640 0.840 109.920 750.960 ;
      RECT 111.880 0.840 112.160 750.960 ;
      RECT 114.120 0.840 114.400 750.960 ;
      RECT 116.360 0.840 116.640 750.960 ;
      RECT 118.600 0.840 118.880 750.960 ;
      RECT 120.840 0.840 121.120 750.960 ;
      RECT 123.080 0.840 123.360 750.960 ;
      RECT 125.320 0.840 125.600 750.960 ;
      RECT 127.560 0.840 127.840 750.960 ;
      RECT 129.800 0.840 130.080 750.960 ;
      RECT 132.040 0.840 132.320 750.960 ;
      RECT 134.280 0.840 134.560 750.960 ;
      RECT 136.520 0.840 136.800 750.960 ;
      RECT 138.760 0.840 139.040 750.960 ;
      RECT 141.000 0.840 141.280 750.960 ;
      RECT 143.240 0.840 143.520 750.960 ;
      RECT 145.480 0.840 145.760 750.960 ;
      RECT 147.720 0.840 148.000 750.960 ;
      RECT 149.960 0.840 150.240 750.960 ;
      RECT 152.200 0.840 152.480 750.960 ;
      RECT 154.440 0.840 154.720 750.960 ;
      RECT 156.680 0.840 156.960 750.960 ;
      RECT 158.920 0.840 159.200 750.960 ;
      RECT 161.160 0.840 161.440 750.960 ;
      RECT 163.400 0.840 163.680 750.960 ;
      RECT 165.640 0.840 165.920 750.960 ;
      RECT 167.880 0.840 168.160 750.960 ;
      RECT 170.120 0.840 170.400 750.960 ;
      RECT 172.360 0.840 172.640 750.960 ;
      RECT 174.600 0.840 174.880 750.960 ;
      RECT 176.840 0.840 177.120 750.960 ;
      RECT 179.080 0.840 179.360 750.960 ;
      RECT 181.320 0.840 181.600 750.960 ;
      RECT 183.560 0.840 183.840 750.960 ;
      RECT 185.800 0.840 186.080 750.960 ;
      RECT 188.040 0.840 188.320 750.960 ;
      RECT 190.280 0.840 190.560 750.960 ;
      RECT 192.520 0.840 192.800 750.960 ;
      RECT 194.760 0.840 195.040 750.960 ;
      RECT 197.000 0.840 197.280 750.960 ;
      RECT 199.240 0.840 199.520 750.960 ;
      RECT 201.480 0.840 201.760 750.960 ;
      RECT 203.720 0.840 204.000 750.960 ;
      RECT 205.960 0.840 206.240 750.960 ;
      RECT 208.200 0.840 208.480 750.960 ;
      RECT 210.440 0.840 210.720 750.960 ;
      RECT 212.680 0.840 212.960 750.960 ;
      RECT 214.920 0.840 215.200 750.960 ;
      RECT 217.160 0.840 217.440 750.960 ;
      RECT 219.400 0.840 219.680 750.960 ;
      RECT 221.640 0.840 221.920 750.960 ;
      RECT 223.880 0.840 224.160 750.960 ;
      RECT 226.120 0.840 226.400 750.960 ;
      RECT 228.360 0.840 228.640 750.960 ;
      RECT 230.600 0.840 230.880 750.960 ;
      RECT 232.840 0.840 233.120 750.960 ;
      RECT 235.080 0.840 235.360 750.960 ;
      RECT 237.320 0.840 237.600 750.960 ;
      RECT 239.560 0.840 239.840 750.960 ;
      RECT 241.800 0.840 242.080 750.960 ;
      RECT 244.040 0.840 244.320 750.960 ;
      RECT 246.280 0.840 246.560 750.960 ;
      RECT 248.520 0.840 248.800 750.960 ;
      RECT 250.760 0.840 251.040 750.960 ;
      RECT 253.000 0.840 253.280 750.960 ;
      RECT 255.240 0.840 255.520 750.960 ;
      RECT 257.480 0.840 257.760 750.960 ;
      RECT 259.720 0.840 260.000 750.960 ;
      RECT 261.960 0.840 262.240 750.960 ;
      RECT 264.200 0.840 264.480 750.960 ;
      RECT 266.440 0.840 266.720 750.960 ;
      RECT 268.680 0.840 268.960 750.960 ;
      RECT 270.920 0.840 271.200 750.960 ;
      RECT 273.160 0.840 273.440 750.960 ;
      RECT 275.400 0.840 275.680 750.960 ;
      RECT 277.640 0.840 277.920 750.960 ;
      RECT 279.880 0.840 280.160 750.960 ;
      RECT 282.120 0.840 282.400 750.960 ;
      RECT 284.360 0.840 284.640 750.960 ;
      RECT 286.600 0.840 286.880 750.960 ;
      RECT 288.840 0.840 289.120 750.960 ;
      RECT 291.080 0.840 291.360 750.960 ;
      RECT 293.320 0.840 293.600 750.960 ;
      RECT 295.560 0.840 295.840 750.960 ;
      RECT 297.800 0.840 298.080 750.960 ;
      RECT 300.040 0.840 300.320 750.960 ;
      RECT 302.280 0.840 302.560 750.960 ;
      RECT 304.520 0.840 304.800 750.960 ;
      RECT 306.760 0.840 307.040 750.960 ;
      RECT 309.000 0.840 309.280 750.960 ;
      RECT 311.240 0.840 311.520 750.960 ;
      RECT 313.480 0.840 313.760 750.960 ;
      RECT 315.720 0.840 316.000 750.960 ;
      RECT 317.960 0.840 318.240 750.960 ;
      RECT 320.200 0.840 320.480 750.960 ;
      RECT 322.440 0.840 322.720 750.960 ;
      RECT 324.680 0.840 324.960 750.960 ;
      RECT 326.920 0.840 327.200 750.960 ;
      RECT 329.160 0.840 329.440 750.960 ;
      RECT 331.400 0.840 331.680 750.960 ;
      RECT 333.640 0.840 333.920 750.960 ;
      RECT 335.880 0.840 336.160 750.960 ;
      RECT 338.120 0.840 338.400 750.960 ;
      RECT 340.360 0.840 340.640 750.960 ;
      RECT 342.600 0.840 342.880 750.960 ;
      RECT 344.840 0.840 345.120 750.960 ;
      RECT 347.080 0.840 347.360 750.960 ;
      RECT 349.320 0.840 349.600 750.960 ;
      RECT 351.560 0.840 351.840 750.960 ;
      RECT 353.800 0.840 354.080 750.960 ;
      RECT 356.040 0.840 356.320 750.960 ;
      RECT 358.280 0.840 358.560 750.960 ;
      RECT 360.520 0.840 360.800 750.960 ;
      RECT 362.760 0.840 363.040 750.960 ;
      RECT 365.000 0.840 365.280 750.960 ;
      RECT 367.240 0.840 367.520 750.960 ;
      RECT 369.480 0.840 369.760 750.960 ;
      RECT 371.720 0.840 372.000 750.960 ;
      RECT 373.960 0.840 374.240 750.960 ;
      RECT 376.200 0.840 376.480 750.960 ;
      RECT 378.440 0.840 378.720 750.960 ;
      RECT 380.680 0.840 380.960 750.960 ;
      RECT 382.920 0.840 383.200 750.960 ;
      RECT 385.160 0.840 385.440 750.960 ;
      RECT 387.400 0.840 387.680 750.960 ;
      RECT 389.640 0.840 389.920 750.960 ;
      RECT 391.880 0.840 392.160 750.960 ;
      RECT 394.120 0.840 394.400 750.960 ;
      RECT 396.360 0.840 396.640 750.960 ;
      RECT 398.600 0.840 398.880 750.960 ;
      RECT 400.840 0.840 401.120 750.960 ;
      RECT 403.080 0.840 403.360 750.960 ;
      RECT 405.320 0.840 405.600 750.960 ;
      RECT 407.560 0.840 407.840 750.960 ;
      RECT 409.800 0.840 410.080 750.960 ;
      RECT 412.040 0.840 412.320 750.960 ;
      RECT 414.280 0.840 414.560 750.960 ;
      RECT 416.520 0.840 416.800 750.960 ;
      RECT 418.760 0.840 419.040 750.960 ;
      RECT 421.000 0.840 421.280 750.960 ;
      RECT 423.240 0.840 423.520 750.960 ;
      RECT 425.480 0.840 425.760 750.960 ;
      RECT 427.720 0.840 428.000 750.960 ;
      RECT 429.960 0.840 430.240 750.960 ;
      RECT 432.200 0.840 432.480 750.960 ;
      RECT 434.440 0.840 434.720 750.960 ;
      RECT 436.680 0.840 436.960 750.960 ;
      RECT 438.920 0.840 439.200 750.960 ;
      RECT 441.160 0.840 441.440 750.960 ;
      RECT 443.400 0.840 443.680 750.960 ;
      RECT 445.640 0.840 445.920 750.960 ;
      RECT 447.880 0.840 448.160 750.960 ;
      RECT 450.120 0.840 450.400 750.960 ;
      RECT 452.360 0.840 452.640 750.960 ;
      RECT 454.600 0.840 454.880 750.960 ;
      RECT 456.840 0.840 457.120 750.960 ;
      RECT 459.080 0.840 459.360 750.960 ;
      RECT 461.320 0.840 461.600 750.960 ;
      RECT 463.560 0.840 463.840 750.960 ;
      RECT 465.800 0.840 466.080 750.960 ;
      RECT 468.040 0.840 468.320 750.960 ;
      RECT 470.280 0.840 470.560 750.960 ;
      RECT 472.520 0.840 472.800 750.960 ;
      RECT 474.760 0.840 475.040 750.960 ;
      RECT 477.000 0.840 477.280 750.960 ;
      RECT 479.240 0.840 479.520 750.960 ;
      RECT 481.480 0.840 481.760 750.960 ;
      RECT 483.720 0.840 484.000 750.960 ;
      RECT 485.960 0.840 486.240 750.960 ;
      RECT 488.200 0.840 488.480 750.960 ;
      RECT 490.440 0.840 490.720 750.960 ;
      RECT 492.680 0.840 492.960 750.960 ;
      RECT 494.920 0.840 495.200 750.960 ;
      RECT 497.160 0.840 497.440 750.960 ;
      RECT 499.400 0.840 499.680 750.960 ;
      RECT 501.640 0.840 501.920 750.960 ;
      RECT 503.880 0.840 504.160 750.960 ;
      RECT 506.120 0.840 506.400 750.960 ;
      RECT 508.360 0.840 508.640 750.960 ;
      RECT 510.600 0.840 510.880 750.960 ;
      RECT 512.840 0.840 513.120 750.960 ;
      RECT 515.080 0.840 515.360 750.960 ;
      RECT 517.320 0.840 517.600 750.960 ;
      RECT 519.560 0.840 519.840 750.960 ;
      RECT 521.800 0.840 522.080 750.960 ;
      RECT 524.040 0.840 524.320 750.960 ;
      RECT 526.280 0.840 526.560 750.960 ;
      RECT 528.520 0.840 528.800 750.960 ;
      RECT 530.760 0.840 531.040 750.960 ;
      RECT 533.000 0.840 533.280 750.960 ;
      RECT 535.240 0.840 535.520 750.960 ;
      RECT 537.480 0.840 537.760 750.960 ;
      RECT 539.720 0.840 540.000 750.960 ;
      RECT 541.960 0.840 542.240 750.960 ;
      RECT 544.200 0.840 544.480 750.960 ;
      RECT 546.440 0.840 546.720 750.960 ;
      RECT 548.680 0.840 548.960 750.960 ;
      RECT 550.920 0.840 551.200 750.960 ;
      RECT 553.160 0.840 553.440 750.960 ;
      RECT 555.400 0.840 555.680 750.960 ;
      RECT 557.640 0.840 557.920 750.960 ;
      RECT 559.880 0.840 560.160 750.960 ;
      RECT 562.120 0.840 562.400 750.960 ;
      RECT 564.360 0.840 564.640 750.960 ;
      RECT 566.600 0.840 566.880 750.960 ;
      RECT 568.840 0.840 569.120 750.960 ;
      RECT 571.080 0.840 571.360 750.960 ;
      RECT 573.320 0.840 573.600 750.960 ;
      RECT 575.560 0.840 575.840 750.960 ;
      RECT 577.800 0.840 578.080 750.960 ;
      RECT 580.040 0.840 580.320 750.960 ;
    END
  END VDD
  OBS
    LAYER metal1 ;
    RECT 0 0 581.970 751.800 ;
    LAYER metal2 ;
    RECT 0 0 581.970 751.800 ;
    LAYER metal3 ;
    RECT 0 0 581.970 751.800 ;
    LAYER metal4 ;
    RECT 0 0 581.970 751.800 ;
    LAYER OVERLAP ;
    RECT 0 0 581.970 751.800 ;
  END
END fakeram_w16_l8192

END LIBRARY
